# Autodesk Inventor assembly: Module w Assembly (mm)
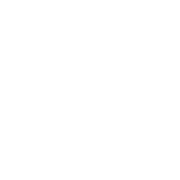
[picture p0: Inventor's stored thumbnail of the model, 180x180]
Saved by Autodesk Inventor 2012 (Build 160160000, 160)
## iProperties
Created: 2006-10
Part Number: Module w Assembly (mm)
Document SubType Name: Assembly
Designer: Wally Jones
Author: Wally Jones
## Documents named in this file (1)
- C:\!Wally\!!AutoCAD Modules!!\!Inventor\Templates\Metric Templates\Modules Assembly (mm).iam
